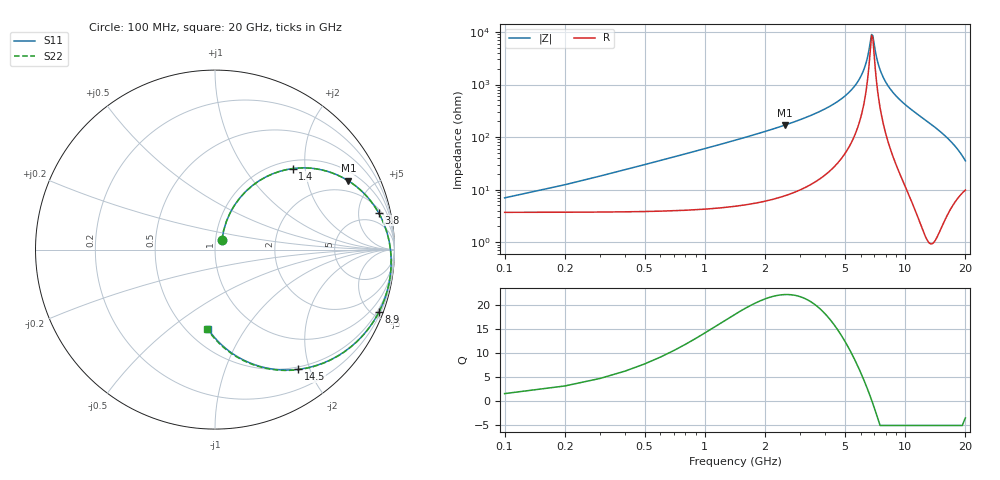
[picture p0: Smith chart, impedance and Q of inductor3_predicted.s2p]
#  Hz  S  RI  R  50
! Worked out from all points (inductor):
!   200 points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, 100 MHz to 20 GHz, reference 50 ohm
!   read as one part in series: L = 9.39 nH near 200 MHz
!   highest Q = 22.1 at 2.5 GHz (marker M1), where L = 10.7 nH
!   self-resonance near 6.8 GHz
!   S11 on the Smith chart (normalised r, x): 100 MHz: 1.07, +0.12; 1.4 GHz: 1.16, +1.72; 3.8 GHz: 2.53, +8.18; 8.9 GHz: 0.35, -5.39; 14.5 GHz: 0.46, -1.82; 20 GHz: 0.63, -0.69
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1e8  0.0386 0.0535  0.9612 -0.0559  0.9612 -0.0559  0.0387 0.0535
3e8  0.0633 0.1565  0.9363 -0.1638  0.9363 -0.1638  0.0633 0.1565
5e8  0.1094 0.2485  0.8899 -0.2606  0.8899 -0.2606  0.1095 0.2484
9e8  0.244 0.3823  0.7543 -0.4037  0.7543 -0.4037  0.2441 0.3822
1.4e9  0.4337 0.4516  0.5632 -0.484  0.5632 -0.484  0.4338 0.4515
2.5e9  0.7429 0.3833  0.2516 -0.4385  0.2516 -0.4385  0.7431 0.3828
3.5e9  0.8851 0.2475  0.108 -0.3238  0.108 -0.3238  0.8852 0.2468
3.8e9  0.9111 0.2062  0.0815 -0.289  0.0815 -0.289  0.9112 0.2054
5.1e9  0.9717 0.0391  0.0189 -0.1512  0.0189 -0.1512  0.9717 0.0379
5.9e9  0.9814 -0.0536  0.00744 -0.0779  0.00744 -0.0779  0.9813 -0.0549
6.4e9  0.9802 -0.108  0.00713 -0.036  0.00713 -0.036  0.98 -0.1095
6.8e9  0.9759 -0.1499  0.00998 -0.00451  0.00998 -0.00451  0.9756 -0.1514
6.9e9  0.9744 -0.1602  0.0111 0.00312  0.0111 0.00312  0.9741 -0.1617
7.3e9  0.9668 -0.2004  0.0169 0.0326  0.0169 0.0326  0.9664 -0.202
7.6e9  0.9595 -0.2297  0.0227 0.0538  0.0227 0.0538  0.959 -0.2314
8.1e9  0.9443 -0.2771  0.0349 0.0871  0.0349 0.0871  0.9437 -0.2789
8.9e9  0.9127 -0.3492  0.0603 0.1359  0.0603 0.1359  0.9119 -0.3512
1.01e10  0.8489 -0.4482  0.1109 0.1981  0.1109 0.1981  0.8477 -0.4503
1.34e10  0.5783 -0.6409  0.3111 0.2879  0.3111 0.2879  0.5758 -0.6432
1.45e10  0.4638 -0.6671  0.3888 0.2844  0.3888 0.2844  0.4609 -0.6693
1.67e10  0.2281 -0.6437  0.5339 0.2213  0.5339 0.2213  0.2244 -0.6453
2e10  -0.0394 -0.4411  0.6565 0.0264  0.6565 0.0264  -0.0437 -0.4414
